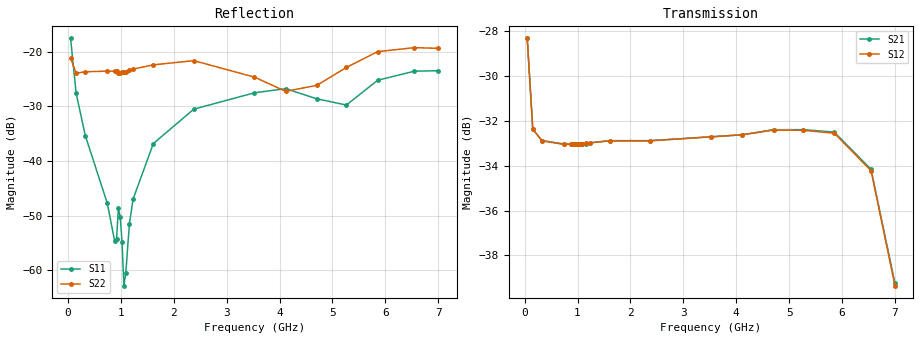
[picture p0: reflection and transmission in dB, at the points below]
! Integrated Device Technology
! Corporate Headquarters
! 6024 Silver Creek Valley Road
! San Jose, CA 95138  USA
! Phone:  1-408-284-8200
! Toll Free:  1-800-223-1366
! Webpage:  http://www.idt.com/
! Timing and RF Division
! 515 Groton Road, Suite 102
! Westford, MA 01886-6024
! Device:  F2258
! Description: Voltage Variable RF Attenuator
! Frequency:  50.0 -  6000.00 MHz
! Package:  3x3 mm Thin QFN Plastic Package: 16 pin
! Ports:  2 RF, 2 DC
!  Pin  1  = NC
!  Pin  2  = NC
!  Pin  3  = RF2  = Port 2
!  Pin  4  = GND
!  Pin  5  = Vdd
!  Pin  6  = NC
!  Pin  7  = VCTRL
!  Pin  8  = NC
!  Pin  9  = GND
!  Pin 10  = RF1  = Port 1
!  Pin 11  = NC
!  Pin 12  = NC
!  Pin 13  = NC
!  Pin 14  = NC
!  Pin 15  = NC
!  Pin 16  = NC
! Vcntrl:  1.780 Volts
! Vdd:  +3.300 Volts
! Current:  1.159 mA
! Data:  The device was measured on a the F2258 evaluation board which has
!  individual transmission lines to the RF pins.  Data was collected
!  using a calibrated network analyzer.  The evaluation board was
!  de-embedded using a TRL calibration technique.
!  The reference plane is the edge of the package pin.
! Misc:  SN 10
!  Action Tracker AT0285
! Date Measured:  2014-12-10
! Date:  2016-01-13  MJV
! Note:
!  Integrated Device Technology supplies this data as a sample of measured
!  data at the package pin for this product.  Your particular data for this
!  product may vary.
!  Data was taken at 25 degrees C.
!  Integrated Device Technology reserves the right to change this data at anytime.
!Freq_(GHz)  S11M_(dB)  S11P_(deg)  S21M_(dB)  S21P_(deg)  S12M_(dB)  S12P_(deg)  S22M_(dB)  S22P_(deg)
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# GHz S dB R 50
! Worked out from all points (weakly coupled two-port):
!   201 points, 50 MHz to 7 GHz, reference 50 ohm
!   highest |S21| = -28.32 dB at 50 MHz (marker M1); lowest = -39.2 dB at 7 GHz (marker M2)
!   lowest |S11| = -62.8 dB at 1.058 GHz (marker M3), VSWR 1.00, Z = 49.9 + j0.0364 ohm
!   |S11| at or under -10 dB: start of sweep to end of sweep
!   |S22| runs from -27.5 to -19.0 dB; largest |S21 - S12| = 0.00016
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0.05  -17.53 -110.5  -28.32 -59.0  -28.32 -59.0  -21.13 -84.1
0.15425  -27.55 -107.0  -32.37 -25.1  -32.36 -25.1  -23.92 -25.8
0.328  -35.33 -113.0  -32.88 -13.8  -32.89 -13.8  -23.65 -11.8
0.745  -47.77 -136.1  -33.03 -9.8  -33.05 -9.8  -23.53 -7.0
0.884  -54.71 167.5  -33.04 -9.7  -33.04 -9.7  -23.54 -7.8
0.91875  -54.31 145.2  -33.04 -9.7  -33.05 -9.7  -23.57 -8.1
0.9535  -48.69 -157.2  -33.05 -9.7  -33.05 -9.7  -23.95 -6.5
0.98825  -50.25 -169.5  -33.04 -9.7  -33.04 -9.8  -23.89 -7.3
1.023  -54.84 177.6  -33.03 -9.8  -33.05 -9.8  -23.76 -7.5
1.05775  -62.83 149.7  -33.03 -9.8  -33.04 -9.8  -23.66 -7.3
1.0925  -60.59 92.6  -33.03 -9.9  -33.03 -9.9  -23.61 -7.5
1.162  -51.49 56.7  -33.01 -10.1  -33.00 -10.1  -23.37 -7.8
1.2315  -46.97 39.2  -32.98 -10.3  -32.98 -10.3  -23.16 -8.2
1.61375  -36.80 30.7  -32.88 -12.7  -32.89 -12.7  -22.38 -10.0
2.37825  -30.50 47.0  -32.88 -17.5  -32.89 -17.5  -21.61 -11.8
3.525  -27.50 91.1  -32.71 -25.6  -32.71 -25.6  -24.63 -14.6
4.11575  -26.74 104.6  -32.62 -30.3  -32.62 -30.2  -27.23 -24.7
4.7065  -28.61 95.3  -32.39 -35.9  -32.41 -35.8  -26.13 -36.4
5.2625  -29.74 53.5  -32.39 -42.0  -32.42 -41.9  -22.86 -41.1
5.85325  -25.21 29.3  -32.50 -51.6  -32.55 -51.5  -19.96 -42.2
6.54825  -23.54 44.7  -34.16 -68.8  -34.22 -68.8  -19.23 -67.4
7  -23.45 84.1  -39.24 -66.7  -39.35 -66.4  -19.35 -123.2
